# The block's outline and pins, enough for the parent to link it.
VERSION 5.8 ;
BUSBITCHARS "[]" ;
DIVIDERCHAR "/" ;
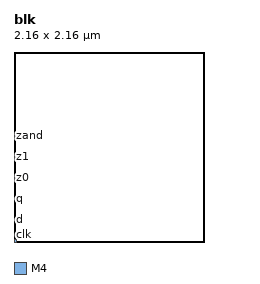
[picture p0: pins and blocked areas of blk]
MACRO blk
  CLASS BLOCK ;
  ORIGIN 0 0 ;
  SIZE 2.16 BY 2.16 ;
  PIN clk DIRECTION INPUT ; USE CLOCK ;
    PORT LAYER M4 ; RECT 0 0.00 0.024 0.024 ; END
  END clk
  PIN d DIRECTION INPUT ; USE SIGNAL ;
    PORT LAYER M4 ; RECT 0 0.24 0.024 0.264 ; END
  END d
  PIN q DIRECTION OUTPUT ; USE SIGNAL ;
    PORT LAYER M4 ; RECT 0 0.48 0.024 0.504 ; END
  END q
  PIN z0 DIRECTION OUTPUT ; USE SIGNAL ;
    PORT LAYER M4 ; RECT 0 0.72 0.024 0.744 ; END
  END z0
  PIN z1 DIRECTION OUTPUT ; USE SIGNAL ;
    PORT LAYER M4 ; RECT 0 0.96 0.024 0.984 ; END
  END z1
  PIN zand DIRECTION OUTPUT ; USE SIGNAL ;
    PORT LAYER M4 ; RECT 0 1.20 0.024 1.224 ; END
  END zand
END blk
END LIBRARY
